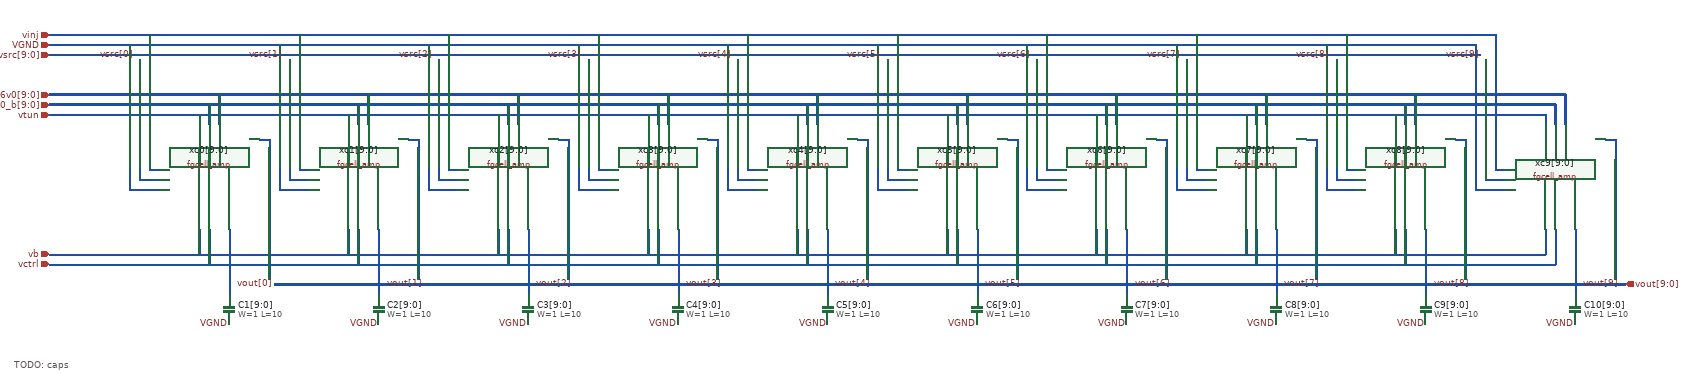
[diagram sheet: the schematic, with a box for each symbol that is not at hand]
v {xschem version=3.4.5 file_version=1.2
}
G {}
K {}
V {}
S {}
E {}
T {TODO: caps} 310 -350 0 0 0.4 0.4 {}
N 680 -840 680 -820 {
lab=vtun}
N 700 -860 700 -820 {
lab=row_en_6v0_b[9:0]
bus=true}
N 720 -880 720 -820 {
lab=row_en_6v0[9:0]
bus=true}
N 580 -730 600 -730 {
lab=vinj}
N 560 -710 600 -710 {
lab=vsrc[0]}
N 540 -690 600 -690 {
lab=VGND}
N 680 -610 680 -560 {
lab=vb}
N 700 -610 700 -540 {
lab=vctrl}
N 380 -1000 3280 -1000 {
lab=vinj}
N 3280 -1000 3280 -730 {
lab=vinj}
N 3280 -730 3300 -730 {
lab=vinj}
N 380 -980 3240 -980 {
lab=VGND}
N 3240 -980 3240 -690 {
lab=VGND}
N 3240 -690 3300 -690 {
lab=VGND}
N 380 -960 3250 -960 {
lab=vsrc[9:0]}
N 580 -1000 580 -730 {
lab=vinj}
N 540 -980 540 -690 {
lab=VGND}
N 560 -950 560 -710 {
lab=vsrc[0]}
N 860 -950 860 -710 {
lab=vsrc[1]}
N 860 -710 900 -710 {
lab=vsrc[1]}
N 880 -730 900 -730 {
lab=vinj}
N 880 -1000 880 -730 {
lab=vinj}
N 840 -690 900 -690 {
lab=VGND}
N 840 -980 840 -690 {
lab=VGND}
N 1180 -730 1200 -730 {
lab=vinj}
N 1160 -710 1200 -710 {
lab=vsrc[2]}
N 1140 -690 1200 -690 {
lab=VGND}
N 1180 -1000 1180 -730 {
lab=vinj}
N 1140 -980 1140 -690 {
lab=VGND}
N 1160 -950 1160 -710 {
lab=vsrc[2]}
N 1480 -730 1500 -730 {
lab=vinj}
N 1460 -710 1500 -710 {
lab=vsrc[3]}
N 1440 -690 1500 -690 {
lab=VGND}
N 1480 -1000 1480 -730 {
lab=vinj}
N 1440 -980 1440 -690 {
lab=VGND}
N 1460 -950 1460 -710 {
lab=vsrc[3]}
N 1780 -730 1800 -730 {
lab=vinj}
N 1760 -710 1800 -710 {
lab=vsrc[4]}
N 1740 -690 1800 -690 {
lab=VGND}
N 1780 -1000 1780 -730 {
lab=vinj}
N 1740 -980 1740 -690 {
lab=VGND}
N 1760 -950 1760 -710 {
lab=vsrc[4]}
N 2080 -730 2100 -730 {
lab=vinj}
N 2060 -710 2100 -710 {
lab=vsrc[5]}
N 2040 -690 2100 -690 {
lab=VGND}
N 2080 -1000 2080 -730 {
lab=vinj}
N 2040 -980 2040 -690 {
lab=VGND}
N 2060 -950 2060 -710 {
lab=vsrc[5]}
N 2380 -730 2400 -730 {
lab=vinj}
N 2360 -710 2400 -710 {
lab=vsrc[6]}
N 2340 -690 2400 -690 {
lab=VGND}
N 2380 -1000 2380 -730 {
lab=vinj}
N 2340 -980 2340 -690 {
lab=VGND}
N 2360 -950 2360 -710 {
lab=vsrc[6]}
N 2680 -730 2700 -730 {
lab=vinj}
N 2660 -710 2700 -710 {
lab=vsrc[7]}
N 2640 -690 2700 -690 {
lab=VGND}
N 2680 -1000 2680 -730 {
lab=vinj}
N 2640 -980 2640 -690 {
lab=VGND}
N 2660 -950 2660 -710 {
lab=vsrc[7]}
N 2980 -730 3000 -730 {
lab=vinj}
N 2960 -710 3000 -710 {
lab=vsrc[8]}
N 2940 -690 3000 -690 {
lab=VGND}
N 2980 -1000 2980 -730 {
lab=vinj}
N 2940 -980 2940 -690 {
lab=VGND}
N 2960 -950 2960 -710 {
lab=vsrc[8]}
N 3260 -950 3260 -710 {
lab=vsrc[9]}
N 3260 -710 3300 -710 {
lab=vsrc[9]}
N 380 -840 3380 -840 {
lab=vtun}
N 380 -860 3400 -860 {
lab=row_en_6v0_b[9:0]
bus=true}
N 380 -880 3420 -880 {
lab=row_en_6v0[9:0]
bus=true}
N 980 -840 980 -820 {
lab=vtun}
N 1000 -860 1000 -820 {
lab=row_en_6v0_b[9:0]
bus=true}
N 1020 -880 1020 -820 {
lab=row_en_6v0[9:0]
bus=true}
N 1280 -840 1280 -820 {
lab=vtun}
N 1300 -860 1300 -820 {
lab=row_en_6v0_b[9:0]
bus=true}
N 1320 -880 1320 -820 {
lab=row_en_6v0[9:0]
bus=true}
N 1580 -840 1580 -820 {
lab=vtun}
N 1600 -860 1600 -820 {
lab=row_en_6v0_b[9:0]
bus=true}
N 1620 -880 1620 -820 {
lab=row_en_6v0[9:0]
bus=true}
N 1880 -840 1880 -820 {
lab=vtun}
N 1900 -860 1900 -820 {
lab=row_en_6v0_b[9:0]
bus=true}
N 1920 -880 1920 -820 {
lab=row_en_6v0[9:0]
bus=true}
N 2180 -840 2180 -820 {
lab=vtun}
N 2200 -860 2200 -820 {
lab=row_en_6v0_b[9:0]
bus=true}
N 2220 -880 2220 -820 {
lab=row_en_6v0[9:0]
bus=true}
N 2480 -840 2480 -820 {
lab=vtun}
N 2500 -860 2500 -820 {
lab=row_en_6v0_b[9:0]
bus=true}
N 2520 -880 2520 -820 {
lab=row_en_6v0[9:0]
bus=true}
N 2780 -840 2780 -820 {
lab=vtun}
N 2800 -860 2800 -820 {
lab=row_en_6v0_b[9:0]
bus=true}
N 2820 -880 2820 -820 {
lab=row_en_6v0[9:0]
bus=true}
N 3080 -840 3080 -820 {
lab=vtun}
N 3100 -860 3100 -820 {
lab=row_en_6v0_b[9:0]
bus=true}
N 3120 -880 3120 -820 {
lab=row_en_6v0[9:0]
bus=true}
N 3380 -840 3380 -820 {
lab=vtun}
N 3400 -860 3400 -820 {
lab=row_en_6v0_b[9:0]
bus=true}
N 3420 -880 3420 -820 {
lab=row_en_6v0[9:0]
bus=true}
N 380 -560 3380 -560 {
lab=vb}
N 380 -540 3400 -540 {
lab=vctrl}
N 980 -610 980 -560 {
lab=vb}
N 1000 -610 1000 -540 {
lab=vctrl}
N 1280 -610 1280 -560 {
lab=vb}
N 1300 -610 1300 -540 {
lab=vctrl}
N 1580 -610 1580 -560 {
lab=vb}
N 1600 -610 1600 -540 {
lab=vctrl}
N 1880 -610 1880 -560 {
lab=vb}
N 1900 -610 1900 -540 {
lab=vctrl}
N 2180 -610 2180 -560 {
lab=vb}
N 2200 -610 2200 -540 {
lab=vctrl}
N 2480 -610 2480 -560 {
lab=vb}
N 2500 -610 2500 -540 {
lab=vctrl}
N 2780 -610 2780 -560 {
lab=vb}
N 2800 -610 2800 -540 {
lab=vctrl}
N 3080 -610 3080 -560 {
lab=vb}
N 3100 -610 3100 -540 {
lab=vctrl}
N 3380 -610 3380 -560 {
lab=vb}
N 3400 -610 3400 -540 {
lab=vctrl}
N 830 -500 3540 -500 {
lab=vout[9:0]
bus=true}
N 820 -790 820 -510 {
lab=vout[0]}
N 800 -790 820 -790 {
lab=vout[0]}
N 1120 -790 1120 -510 {
lab=vout[1]}
N 1100 -790 1120 -790 {
lab=vout[1]}
N 1420 -790 1420 -510 {
lab=vout[2]}
N 1400 -790 1420 -790 {
lab=vout[2]}
N 1720 -790 1720 -510 {
lab=vout[3]}
N 1700 -790 1720 -790 {
lab=vout[3]}
N 2020 -790 2020 -510 {
lab=vout[4]}
N 2000 -790 2020 -790 {
lab=vout[4]}
N 2320 -790 2320 -510 {
lab=vout[5]}
N 2300 -790 2320 -790 {
lab=vout[5]}
N 2620 -790 2620 -510 {
lab=vout[6]}
N 2600 -790 2620 -790 {
lab=vout[6]}
N 2920 -790 2920 -510 {
lab=vout[7]}
N 2900 -790 2920 -790 {
lab=vout[7]}
N 3220 -790 3220 -510 {
lab=vout[8]}
N 3200 -790 3220 -790 {
lab=vout[8]}
N 3520 -790 3520 -510 {
lab=vout[1]}
N 3500 -790 3520 -790 {
lab=vout[1]}
N 740 -610 740 -480 {
lab=#net1}
N 1040 -610 1040 -480 {
lab=#net2}
N 1340 -610 1340 -480 {
lab=#net3}
N 1640 -610 1640 -480 {
lab=#net4}
N 1940 -610 1940 -480 {
lab=#net5}
N 2240 -610 2240 -480 {
lab=#net6}
N 2540 -610 2540 -480 {
lab=#net7}
N 2840 -610 2840 -480 {
lab=#net8}
N 3140 -610 3140 -480 {
lab=#net8}
N 3440 -610 3440 -480 {
lab=#net8}
C {fgcell_amp.sym} 700 -710 0 0 {name=xc0[9:0]}
C {fgcell_amp.sym} 1000 -710 0 0 {name=xc1[9:0]}
C {devices/ipin.sym} 380 -840 0 0 {name=p1 lab=vtun}
C {devices/ipin.sym} 380 -1000 0 0 {name=p3 lab=vinj}
C {devices/ipin.sym} 380 -980 0 0 {name=p4 lab=VGND}
C {devices/ipin.sym} 380 -560 0 0 {name=p5 lab=vb}
C {devices/ipin.sym} 380 -880 0 0 {name=p6 lab=row_en_6v0[9:0]}
C {devices/ipin.sym} 380 -860 0 0 {name=p7 lab=row_en_6v0_b[9:0]}
C {devices/ipin.sym} 380 -540 0 0 {name=p8 lab=vctrl}
C {devices/ipin.sym} 380 -960 0 0 {name=p9 lab=vsrc[9:0]}
C {devices/opin.sym} 3540 -500 0 0 {name=p2 lab=vout[9:0]}
C {devices/bus_connect.sym} 550 -960 2 1 {name=l1 lab=vsrc[0]}
C {devices/bus_connect.sym} 850 -960 2 1 {name=l2 lab=vsrc[1]}
C {devices/bus_connect.sym} 830 -500 3 0 {name=l3 lab=vout[0]}
C {devices/bus_connect.sym} 1130 -500 3 0 {name=l4 lab=vout[1]}
C {fgcell_amp.sym} 1300 -710 0 0 {name=xc2[9:0]}
C {fgcell_amp.sym} 1600 -710 0 0 {name=xc3[9:0]}
C {fgcell_amp.sym} 1900 -710 0 0 {name=xc4[9:0]}
C {fgcell_amp.sym} 2200 -710 0 0 {name=xc5[9:0]}
C {fgcell_amp.sym} 2500 -710 0 0 {name=xc6[9:0]}
C {fgcell_amp.sym} 2800 -710 0 0 {name=xc7[9:0]}
C {fgcell_amp.sym} 3100 -710 0 0 {name=xc8[9:0]}
C {fgcell_amp.sym} 3400 -710 0 0 {name=xc9[9:0]}
C {devices/bus_connect.sym} 1150 -960 2 1 {name=l5 lab=vsrc[2]}
C {devices/bus_connect.sym} 1450 -960 2 1 {name=l6 lab=vsrc[3]}
C {devices/bus_connect.sym} 1750 -960 2 1 {name=l7 lab=vsrc[4]}
C {devices/bus_connect.sym} 2050 -960 2 1 {name=l8 lab=vsrc[5]}
C {devices/bus_connect.sym} 2350 -960 2 1 {name=l9 lab=vsrc[6]}
C {devices/bus_connect.sym} 2650 -960 2 1 {name=l10 lab=vsrc[7]}
C {devices/bus_connect.sym} 2950 -960 2 1 {name=l11 lab=vsrc[8]}
C {devices/bus_connect.sym} 3250 -960 2 1 {name=l12 lab=vsrc[9]}
C {devices/bus_connect.sym} 1430 -500 3 0 {name=l13 lab=vout[2]}
C {devices/bus_connect.sym} 1730 -500 3 0 {name=l14 lab=vout[3]}
C {devices/bus_connect.sym} 2030 -500 3 0 {name=l15 lab=vout[4]}
C {devices/bus_connect.sym} 2330 -500 3 0 {name=l16 lab=vout[5]}
C {devices/bus_connect.sym} 2630 -500 3 0 {name=l17 lab=vout[6]}
C {devices/bus_connect.sym} 2930 -500 3 0 {name=l18 lab=vout[7]}
C {devices/bus_connect.sym} 3230 -500 3 0 {name=l19 lab=vout[8]}
C {devices/bus_connect.sym} 3530 -500 3 0 {name=l20 lab=vout[9]}
C {sky130_fd_pr/cap_mim_m3_1.sym} 740 -450 0 0 {name=C1[9:0] model=cap_mim_m3_1 W=1 L=10 MF=1 spiceprefix=X}
C {devices/lab_pin.sym} 740 -420 3 0 {name=p10 sig_type=std_logic lab=VGND
L=10}
C {sky130_fd_pr/cap_mim_m3_1.sym} 1040 -450 0 0 {name=C2[9:0] model=cap_mim_m3_1 W=1 L=10 MF=1 spiceprefix=X}
C {devices/lab_pin.sym} 1040 -420 3 0 {name=p11 sig_type=std_logic lab=VGND
L=10}
C {sky130_fd_pr/cap_mim_m3_1.sym} 1340 -450 0 0 {name=C3[9:0] model=cap_mim_m3_1 W=1 L=10 MF=1 spiceprefix=X}
C {devices/lab_pin.sym} 1340 -420 3 0 {name=p12 sig_type=std_logic lab=VGND
L=10}
C {sky130_fd_pr/cap_mim_m3_1.sym} 1640 -450 0 0 {name=C4[9:0] model=cap_mim_m3_1 W=1 L=10 MF=1 spiceprefix=X}
C {devices/lab_pin.sym} 1640 -420 3 0 {name=p13 sig_type=std_logic lab=VGND
L=10}
C {sky130_fd_pr/cap_mim_m3_1.sym} 1940 -450 0 0 {name=C5[9:0] model=cap_mim_m3_1 W=1 L=10 MF=1 spiceprefix=X}
C {devices/lab_pin.sym} 1940 -420 3 0 {name=p14 sig_type=std_logic lab=VGND
L=10}
C {sky130_fd_pr/cap_mim_m3_1.sym} 2240 -450 0 0 {name=C6[9:0] model=cap_mim_m3_1 W=1 L=10 MF=1 spiceprefix=X}
C {devices/lab_pin.sym} 2240 -420 3 0 {name=p15 sig_type=std_logic lab=VGND
L=10}
C {sky130_fd_pr/cap_mim_m3_1.sym} 2540 -450 0 0 {name=C7[9:0] model=cap_mim_m3_1 W=1 L=10 MF=1 spiceprefix=X}
C {devices/lab_pin.sym} 2540 -420 3 0 {name=p16 sig_type=std_logic lab=VGND
L=10}
C {sky130_fd_pr/cap_mim_m3_1.sym} 2840 -450 0 0 {name=C8[9:0] model=cap_mim_m3_1 W=1 L=10 MF=1 spiceprefix=X}
C {devices/lab_pin.sym} 2840 -420 3 0 {name=p17 sig_type=std_logic lab=VGND
L=10}
C {sky130_fd_pr/cap_mim_m3_1.sym} 3140 -450 0 0 {name=C9[9:0] model=cap_mim_m3_1 W=1 L=10 MF=1 spiceprefix=X}
C {devices/lab_pin.sym} 3140 -420 3 0 {name=p18 sig_type=std_logic lab=VGND
L=10}
C {sky130_fd_pr/cap_mim_m3_1.sym} 3440 -450 0 0 {name=C10[9:0] model=cap_mim_m3_1 W=1 L=10 MF=1 spiceprefix=X}
C {devices/lab_pin.sym} 3440 -420 3 0 {name=p19 sig_type=std_logic lab=VGND
L=10}
